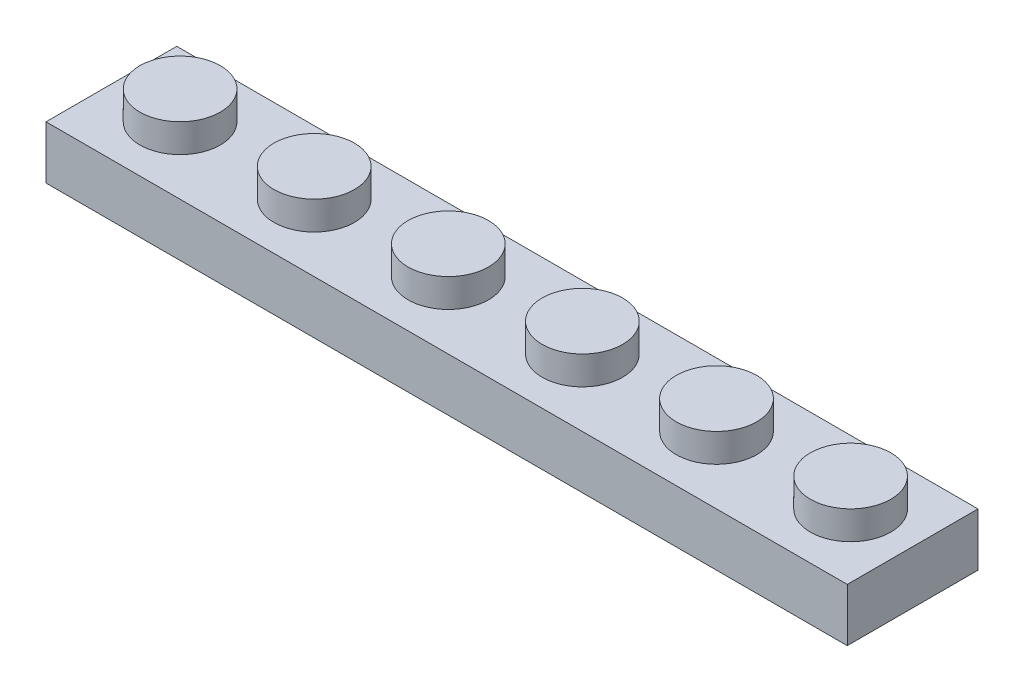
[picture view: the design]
ISO-10303-21;
HEADER;
FILE_DESCRIPTION(('STEP AP214'),'2;1');
FILE_NAME('part.step','',(''),(''),'','','');
FILE_SCHEMA(('AUTOMOTIVE_DESIGN { 1 0 10303 214 1 1 1 1 }'));
ENDSEC;
DATA;
#1=APPLICATION_CONTEXT('core data for automotive mechanical design processes');
#2=APPLICATION_PROTOCOL_DEFINITION('international standard','automotive_design',2000,#1);
#3=PRODUCT_CONTEXT('',#1,'mechanical');
#4=PRODUCT('Part','Part','',(#3));
#5=PRODUCT_RELATED_PRODUCT_CATEGORY('part','',(#4));
#6=PRODUCT_DEFINITION_FORMATION('','',#4);
#7=PRODUCT_DEFINITION_CONTEXT('part definition',#1,'design');
#8=PRODUCT_DEFINITION('design','',#6,#7);
#9=PRODUCT_DEFINITION_SHAPE('','',#8);
#10=(LENGTH_UNIT() NAMED_UNIT(*) SI_UNIT(.MILLI.,.METRE.));
#11=(NAMED_UNIT(*) PLANE_ANGLE_UNIT() SI_UNIT($,.RADIAN.));
#12=(NAMED_UNIT(*) SI_UNIT($,.STERADIAN.) SOLID_ANGLE_UNIT());
#13=UNCERTAINTY_MEASURE_WITH_UNIT(LENGTH_MEASURE(1.E-05),#10,'distance_accuracy_value','');
#14=(GEOMETRIC_REPRESENTATION_CONTEXT(3) GLOBAL_UNCERTAINTY_ASSIGNED_CONTEXT((#13)) GLOBAL_UNIT_ASSIGNED_CONTEXT((#10,
#11,#12)) REPRESENTATION_CONTEXT('',''));
#15=CARTESIAN_POINT('',(0.,0.,0.));
#16=DIRECTION('',(0.,0.,1.));
#17=DIRECTION('',(1.,0.,0.));
#18=AXIS2_PLACEMENT_3D('',#15,#16,#17);
#19=CARTESIAN_POINT('',(0.,3.166,-7.8));
#20=DIRECTION('',(0.,-1.,0.));
#21=DIRECTION('',(0.,0.,-1.));
#22=AXIS2_PLACEMENT_3D('',#19,#20,#21);
#23=PLANE('',#22);
#24=CARTESIAN_POINT('',(36.,3.166,-4.));
#25=DIRECTION('',(0.,-1.,0.));
#26=DIRECTION('',(0.,0.,-1.));
#27=AXIS2_PLACEMENT_3D('',#24,#25,#26);
#28=CIRCLE('',#27,2.4);
#29=CARTESIAN_POINT('',(36.,3.166,-6.4));
#30=VERTEX_POINT('',#29);
#31=EDGE_CURVE('E356',#30,#30,#28,.F.);
#32=ORIENTED_EDGE('',*,*,#31,.F.);
#33=EDGE_LOOP('',(#32));
#34=FACE_BOUND('',#33,.T.);
#35=CARTESIAN_POINT('',(20.,3.166,-4.));
#36=DIRECTION('',(0.,-1.,0.));
#37=DIRECTION('',(0.,0.,-1.));
#38=AXIS2_PLACEMENT_3D('',#35,#36,#37);
#39=CIRCLE('',#38,2.4);
#40=CARTESIAN_POINT('',(20.,3.166,-6.4));
#41=VERTEX_POINT('',#40);
#42=EDGE_CURVE('E350',#41,#41,#39,.F.);
#43=ORIENTED_EDGE('',*,*,#42,.F.);
#44=EDGE_LOOP('',(#43));
#45=FACE_BOUND('',#44,.T.);
#46=CARTESIAN_POINT('',(4.,3.166,-4.));
#47=DIRECTION('',(0.,-1.,0.));
#48=DIRECTION('',(0.,0.,-1.));
#49=AXIS2_PLACEMENT_3D('',#46,#47,#48);
#50=CIRCLE('',#49,2.4);
#51=CARTESIAN_POINT('',(4.,3.166,-6.4));
#52=VERTEX_POINT('',#51);
#53=EDGE_CURVE('E344',#52,#52,#50,.F.);
#54=ORIENTED_EDGE('',*,*,#53,.F.);
#55=EDGE_LOOP('',(#54));
#56=FACE_BOUND('',#55,.T.);
#57=DIRECTION('',(0.,0.,1.));
#58=VECTOR('',#57,1.);
#59=CARTESIAN_POINT('',(0.,3.166,0.));
#60=LINE('',#59,#58);
#61=CARTESIAN_POINT('',(0.,3.166,-7.8));
#62=VERTEX_POINT('',#61);
#63=CARTESIAN_POINT('',(0.,3.166,0.));
#64=VERTEX_POINT('',#63);
#65=EDGE_CURVE('E315',#62,#64,#60,.T.);
#66=ORIENTED_EDGE('',*,*,#65,.T.);
#67=DIRECTION('',(1.,0.,0.));
#68=VECTOR('',#67,1.);
#69=CARTESIAN_POINT('',(0.,3.166,0.));
#70=LINE('',#69,#68);
#71=CARTESIAN_POINT('',(47.8,3.166,0.));
#72=VERTEX_POINT('',#71);
#73=EDGE_CURVE('E318',#64,#72,#70,.T.);
#74=ORIENTED_EDGE('',*,*,#73,.T.);
#75=DIRECTION('',(0.,0.,-1.));
#76=VECTOR('',#75,1.);
#77=CARTESIAN_POINT('',(47.8,3.166,0.));
#78=LINE('',#77,#76);
#79=CARTESIAN_POINT('',(47.8,3.166,-7.8));
#80=VERTEX_POINT('',#79);
#81=EDGE_CURVE('E321',#72,#80,#78,.T.);
#82=ORIENTED_EDGE('',*,*,#81,.T.);
#83=DIRECTION('',(-1.,0.,0.));
#84=VECTOR('',#83,1.);
#85=CARTESIAN_POINT('',(0.,3.166,-7.8));
#86=LINE('',#85,#84);
#87=EDGE_CURVE('E323',#80,#62,#86,.T.);
#88=ORIENTED_EDGE('',*,*,#87,.T.);
#89=EDGE_LOOP('',(#66,#74,#82,#88));
#90=FACE_BOUND('',#89,.T.);
#91=CARTESIAN_POINT('',(12.,3.166,-4.));
#92=DIRECTION('',(0.,-1.,0.));
#93=DIRECTION('',(0.,0.,-1.));
#94=AXIS2_PLACEMENT_3D('',#91,#92,#93);
#95=CIRCLE('',#94,2.4);
#96=CARTESIAN_POINT('',(12.,3.166,-6.4));
#97=VERTEX_POINT('',#96);
#98=EDGE_CURVE('E347',#97,#97,#95,.F.);
#99=ORIENTED_EDGE('',*,*,#98,.F.);
#100=EDGE_LOOP('',(#99));
#101=FACE_BOUND('',#100,.T.);
#102=CARTESIAN_POINT('',(28.,3.166,-4.));
#103=DIRECTION('',(0.,-1.,0.));
#104=DIRECTION('',(0.,0.,-1.));
#105=AXIS2_PLACEMENT_3D('',#102,#103,#104);
#106=CIRCLE('',#105,2.4);
#107=CARTESIAN_POINT('',(28.,3.166,-6.4));
#108=VERTEX_POINT('',#107);
#109=EDGE_CURVE('E353',#108,#108,#106,.F.);
#110=ORIENTED_EDGE('',*,*,#109,.F.);
#111=EDGE_LOOP('',(#110));
#112=FACE_BOUND('',#111,.T.);
#113=CARTESIAN_POINT('',(44.,3.166,-4.));
#114=DIRECTION('',(0.,-1.,0.));
#115=DIRECTION('',(0.,0.,-1.));
#116=AXIS2_PLACEMENT_3D('',#113,#114,#115);
#117=CIRCLE('',#116,2.4);
#118=CARTESIAN_POINT('',(44.,3.166,-6.4));
#119=VERTEX_POINT('',#118);
#120=EDGE_CURVE('E359',#119,#119,#117,.F.);
#121=ORIENTED_EDGE('',*,*,#120,.F.);
#122=EDGE_LOOP('',(#121));
#123=FACE_BOUND('',#122,.T.);
#124=ADVANCED_FACE('F37',(#34,#45,#56,#90,#101,#112,#123),#23,.F.);
#125=CARTESIAN_POINT('',(0.,3.166,0.));
#126=DIRECTION('',(1.,0.,0.));
#127=DIRECTION('',(0.,0.,-1.));
#128=AXIS2_PLACEMENT_3D('',#125,#126,#127);
#129=PLANE('',#128);
#130=DIRECTION('',(0.,0.,1.));
#131=VECTOR('',#130,1.);
#132=CARTESIAN_POINT('',(0.,0.,0.));
#133=LINE('',#132,#131);
#134=CARTESIAN_POINT('',(0.,0.,-7.8));
#135=VERTEX_POINT('',#134);
#136=CARTESIAN_POINT('',(0.,0.,0.));
#137=VERTEX_POINT('',#136);
#138=EDGE_CURVE('E314',#135,#137,#133,.T.);
#139=ORIENTED_EDGE('',*,*,#138,.T.);
#140=DIRECTION('',(0.,-1.,0.));
#141=VECTOR('',#140,1.);
#142=CARTESIAN_POINT('',(0.,3.166,0.));
#143=LINE('',#142,#141);
#144=EDGE_CURVE('E341',#64,#137,#143,.T.);
#145=ORIENTED_EDGE('',*,*,#144,.F.);
#146=ORIENTED_EDGE('',*,*,#65,.F.);
#147=DIRECTION('',(0.,-1.,0.));
#148=VECTOR('',#147,1.);
#149=CARTESIAN_POINT('',(0.,3.166,-7.8));
#150=LINE('',#149,#148);
#151=EDGE_CURVE('E325',#62,#135,#150,.T.);
#152=ORIENTED_EDGE('',*,*,#151,.T.);
#153=EDGE_LOOP('',(#139,#145,#146,#152));
#154=FACE_BOUND('',#153,.T.);
#155=ADVANCED_FACE('F519',(#154),#129,.F.);
#156=CARTESIAN_POINT('',(0.,3.166,0.));
#157=DIRECTION('',(0.,0.,-1.));
#158=DIRECTION('',(-1.,0.,0.));
#159=AXIS2_PLACEMENT_3D('',#156,#157,#158);
#160=PLANE('',#159);
#161=DIRECTION('',(1.,0.,0.));
#162=VECTOR('',#161,1.);
#163=CARTESIAN_POINT('',(0.,0.,0.));
#164=LINE('',#163,#162);
#165=CARTESIAN_POINT('',(47.8,0.,0.));
#166=VERTEX_POINT('',#165);
#167=EDGE_CURVE('E328',#137,#166,#164,.T.);
#168=ORIENTED_EDGE('',*,*,#167,.T.);
#169=DIRECTION('',(0.,-1.,0.));
#170=VECTOR('',#169,1.);
#171=CARTESIAN_POINT('',(47.8,3.166,0.));
#172=LINE('',#171,#170);
#173=EDGE_CURVE('E338',#72,#166,#172,.T.);
#174=ORIENTED_EDGE('',*,*,#173,.F.);
#175=ORIENTED_EDGE('',*,*,#73,.F.);
#176=ORIENTED_EDGE('',*,*,#144,.T.);
#177=EDGE_LOOP('',(#168,#174,#175,#176));
#178=FACE_BOUND('',#177,.T.);
#179=ADVANCED_FACE('F524',(#178),#160,.F.);
#180=CARTESIAN_POINT('',(47.8,3.166,0.));
#181=DIRECTION('',(-1.,0.,0.));
#182=DIRECTION('',(0.,0.,1.));
#183=AXIS2_PLACEMENT_3D('',#180,#181,#182);
#184=PLANE('',#183);
#185=DIRECTION('',(0.,0.,-1.));
#186=VECTOR('',#185,1.);
#187=CARTESIAN_POINT('',(47.8,0.,0.));
#188=LINE('',#187,#186);
#189=CARTESIAN_POINT('',(47.8,0.,-7.8));
#190=VERTEX_POINT('',#189);
#191=EDGE_CURVE('E330',#166,#190,#188,.T.);
#192=ORIENTED_EDGE('',*,*,#191,.T.);
#193=DIRECTION('',(0.,-1.,0.));
#194=VECTOR('',#193,1.);
#195=CARTESIAN_POINT('',(47.8,3.166,-7.8));
#196=LINE('',#195,#194);
#197=EDGE_CURVE('E335',#80,#190,#196,.T.);
#198=ORIENTED_EDGE('',*,*,#197,.F.);
#199=ORIENTED_EDGE('',*,*,#81,.F.);
#200=ORIENTED_EDGE('',*,*,#173,.T.);
#201=EDGE_LOOP('',(#192,#198,#199,#200));
#202=FACE_BOUND('',#201,.T.);
#203=ADVANCED_FACE('F513',(#202),#184,.F.);
#204=CARTESIAN_POINT('',(0.,3.166,-7.8));
#205=DIRECTION('',(0.,0.,1.));
#206=DIRECTION('',(1.,0.,0.));
#207=AXIS2_PLACEMENT_3D('',#204,#205,#206);
#208=PLANE('',#207);
#209=DIRECTION('',(-1.,0.,0.));
#210=VECTOR('',#209,1.);
#211=CARTESIAN_POINT('',(0.,0.,-7.8));
#212=LINE('',#211,#210);
#213=EDGE_CURVE('E319',#190,#135,#212,.T.);
#214=ORIENTED_EDGE('',*,*,#213,.T.);
#215=ORIENTED_EDGE('',*,*,#151,.F.);
#216=ORIENTED_EDGE('',*,*,#87,.F.);
#217=ORIENTED_EDGE('',*,*,#197,.T.);
#218=EDGE_LOOP('',(#214,#215,#216,#217));
#219=FACE_BOUND('',#218,.T.);
#220=ADVANCED_FACE('F503',(#219),#208,.F.);
#221=CARTESIAN_POINT('',(0.,0.,-7.8));
#222=DIRECTION('',(0.,-1.,0.));
#223=DIRECTION('',(0.,0.,-1.));
#224=AXIS2_PLACEMENT_3D('',#221,#222,#223);
#225=PLANE('',#224);
#226=DIRECTION('',(0.,0.,-1.));
#227=VECTOR('',#226,1.);
#228=CARTESIAN_POINT('',(33.55,0.,-1.55));
#229=LINE('',#228,#227);
#230=CARTESIAN_POINT('',(33.55,0.,-1.55));
#231=VERTEX_POINT('',#230);
#232=CARTESIAN_POINT('',(33.55,0.,-6.35));
#233=VERTEX_POINT('',#232);
#234=EDGE_CURVE('E249',#231,#233,#229,.T.);
#235=ORIENTED_EDGE('',*,*,#234,.F.);
#236=DIRECTION('',(-1.,0.,0.));
#237=VECTOR('',#236,1.);
#238=CARTESIAN_POINT('',(33.55,0.,-1.55));
#239=LINE('',#238,#237);
#240=CARTESIAN_POINT('',(38.35,0.,-1.55));
#241=VERTEX_POINT('',#240);
#242=EDGE_CURVE('E259',#241,#231,#239,.T.);
#243=ORIENTED_EDGE('',*,*,#242,.F.);
#244=DIRECTION('',(0.,0.,1.));
#245=VECTOR('',#244,1.);
#246=CARTESIAN_POINT('',(38.35,0.,-1.55));
#247=LINE('',#246,#245);
#248=CARTESIAN_POINT('',(38.35,0.,-6.35));
#249=VERTEX_POINT('',#248);
#250=EDGE_CURVE('E250',#249,#241,#247,.T.);
#251=ORIENTED_EDGE('',*,*,#250,.F.);
#252=DIRECTION('',(1.,0.,0.));
#253=VECTOR('',#252,1.);
#254=CARTESIAN_POINT('',(33.55,0.,-6.35));
#255=LINE('',#254,#253);
#256=EDGE_CURVE('E235',#233,#249,#255,.T.);
#257=ORIENTED_EDGE('',*,*,#256,.F.);
#258=EDGE_LOOP('',(#235,#243,#251,#257));
#259=FACE_BOUND('',#258,.T.);
#260=DIRECTION('',(0.,0.,-1.));
#261=VECTOR('',#260,1.);
#262=CARTESIAN_POINT('',(41.55,0.,-1.55));
#263=LINE('',#262,#261);
#264=CARTESIAN_POINT('',(41.55,0.,-1.55));
#265=VERTEX_POINT('',#264);
#266=CARTESIAN_POINT('',(41.55,0.,-6.35));
#267=VERTEX_POINT('',#266);
#268=EDGE_CURVE('E279',#265,#267,#263,.T.);
#269=ORIENTED_EDGE('',*,*,#268,.F.);
#270=DIRECTION('',(-1.,0.,0.));
#271=VECTOR('',#270,1.);
#272=CARTESIAN_POINT('',(41.55,0.,-1.55));
#273=LINE('',#272,#271);
#274=CARTESIAN_POINT('',(46.35,0.,-1.55));
#275=VERTEX_POINT('',#274);
#276=EDGE_CURVE('E284',#275,#265,#273,.T.);
#277=ORIENTED_EDGE('',*,*,#276,.F.);
#278=DIRECTION('',(0.,0.,1.));
#279=VECTOR('',#278,1.);
#280=CARTESIAN_POINT('',(46.35,0.,-1.55));
#281=LINE('',#280,#279);
#282=CARTESIAN_POINT('',(46.35,0.,-6.35));
#283=VERTEX_POINT('',#282);
#284=EDGE_CURVE('E298',#283,#275,#281,.T.);
#285=ORIENTED_EDGE('',*,*,#284,.F.);
#286=DIRECTION('',(1.,0.,0.));
#287=VECTOR('',#286,1.);
#288=CARTESIAN_POINT('',(41.55,0.,-6.35));
#289=LINE('',#288,#287);
#290=EDGE_CURVE('E295',#267,#283,#289,.T.);
#291=ORIENTED_EDGE('',*,*,#290,.F.);
#292=EDGE_LOOP('',(#269,#277,#285,#291));
#293=FACE_BOUND('',#292,.T.);
#294=ORIENTED_EDGE('',*,*,#138,.F.);
#295=ORIENTED_EDGE('',*,*,#213,.F.);
#296=ORIENTED_EDGE('',*,*,#191,.F.);
#297=ORIENTED_EDGE('',*,*,#167,.F.);
#298=EDGE_LOOP('',(#294,#295,#296,#297));
#299=FACE_BOUND('',#298,.T.);
#300=DIRECTION('',(0.,0.,-1.));
#301=VECTOR('',#300,1.);
#302=CARTESIAN_POINT('',(25.55,0.,-1.55));
#303=LINE('',#302,#301);
#304=CARTESIAN_POINT('',(25.55,0.,-1.55));
#305=VERTEX_POINT('',#304);
#306=CARTESIAN_POINT('',(25.55,0.,-6.35));
#307=VERTEX_POINT('',#306);
#308=EDGE_CURVE('E362',#305,#307,#303,.T.);
#309=ORIENTED_EDGE('',*,*,#308,.F.);
#310=DIRECTION('',(-1.,0.,0.));
#311=VECTOR('',#310,1.);
#312=CARTESIAN_POINT('',(25.55,0.,-1.55));
#313=LINE('',#312,#311);
#314=CARTESIAN_POINT('',(30.35,0.,-1.55));
#315=VERTEX_POINT('',#314);
#316=EDGE_CURVE('E364',#315,#305,#313,.T.);
#317=ORIENTED_EDGE('',*,*,#316,.F.);
#318=DIRECTION('',(0.,0.,1.));
#319=VECTOR('',#318,1.);
#320=CARTESIAN_POINT('',(30.35,0.,-1.55));
#321=LINE('',#320,#319);
#322=CARTESIAN_POINT('',(30.35,0.,-6.35));
#323=VERTEX_POINT('',#322);
#324=EDGE_CURVE('E367',#323,#315,#321,.T.);
#325=ORIENTED_EDGE('',*,*,#324,.F.);
#326=DIRECTION('',(1.,0.,0.));
#327=VECTOR('',#326,1.);
#328=CARTESIAN_POINT('',(25.55,0.,-6.35));
#329=LINE('',#328,#327);
#330=EDGE_CURVE('E370',#307,#323,#329,.T.);
#331=ORIENTED_EDGE('',*,*,#330,.F.);
#332=EDGE_LOOP('',(#309,#317,#325,#331));
#333=FACE_BOUND('',#332,.T.);
#334=DIRECTION('',(0.,0.,-1.));
#335=VECTOR('',#334,1.);
#336=CARTESIAN_POINT('',(17.55,0.,-1.55));
#337=LINE('',#336,#335);
#338=CARTESIAN_POINT('',(17.55,0.,-1.55));
#339=VERTEX_POINT('',#338);
#340=CARTESIAN_POINT('',(17.55,0.,-6.35));
#341=VERTEX_POINT('',#340);
#342=EDGE_CURVE('E397',#339,#341,#337,.T.);
#343=ORIENTED_EDGE('',*,*,#342,.F.);
#344=DIRECTION('',(-1.,0.,0.));
#345=VECTOR('',#344,1.);
#346=CARTESIAN_POINT('',(17.55,0.,-1.55));
#347=LINE('',#346,#345);
#348=CARTESIAN_POINT('',(22.35,0.,-1.55));
#349=VERTEX_POINT('',#348);
#350=EDGE_CURVE('E399',#349,#339,#347,.T.);
#351=ORIENTED_EDGE('',*,*,#350,.F.);
#352=DIRECTION('',(0.,0.,1.));
#353=VECTOR('',#352,1.);
#354=CARTESIAN_POINT('',(22.35,0.,-1.55));
#355=LINE('',#354,#353);
#356=CARTESIAN_POINT('',(22.35,0.,-6.35));
#357=VERTEX_POINT('',#356);
#358=EDGE_CURVE('E402',#357,#349,#355,.T.);
#359=ORIENTED_EDGE('',*,*,#358,.F.);
#360=DIRECTION('',(1.,0.,0.));
#361=VECTOR('',#360,1.);
#362=CARTESIAN_POINT('',(17.55,0.,-6.35));
#363=LINE('',#362,#361);
#364=EDGE_CURVE('E405',#341,#357,#363,.T.);
#365=ORIENTED_EDGE('',*,*,#364,.F.);
#366=EDGE_LOOP('',(#343,#351,#359,#365));
#367=FACE_BOUND('',#366,.T.);
#368=DIRECTION('',(0.,0.,-1.));
#369=VECTOR('',#368,1.);
#370=CARTESIAN_POINT('',(9.55,0.,-1.55));
#371=LINE('',#370,#369);
#372=CARTESIAN_POINT('',(9.55,0.,-1.55));
#373=VERTEX_POINT('',#372);
#374=CARTESIAN_POINT('',(9.55,0.,-6.35));
#375=VERTEX_POINT('',#374);
#376=EDGE_CURVE('E432',#373,#375,#371,.T.);
#377=ORIENTED_EDGE('',*,*,#376,.F.);
#378=DIRECTION('',(-1.,0.,0.));
#379=VECTOR('',#378,1.);
#380=CARTESIAN_POINT('',(9.55,0.,-1.55));
#381=LINE('',#380,#379);
#382=CARTESIAN_POINT('',(14.35,0.,-1.55));
#383=VERTEX_POINT('',#382);
#384=EDGE_CURVE('E434',#383,#373,#381,.T.);
#385=ORIENTED_EDGE('',*,*,#384,.F.);
#386=DIRECTION('',(0.,0.,1.));
#387=VECTOR('',#386,1.);
#388=CARTESIAN_POINT('',(14.35,0.,-1.55));
#389=LINE('',#388,#387);
#390=CARTESIAN_POINT('',(14.35,0.,-6.35));
#391=VERTEX_POINT('',#390);
#392=EDGE_CURVE('E437',#391,#383,#389,.T.);
#393=ORIENTED_EDGE('',*,*,#392,.F.);
#394=DIRECTION('',(1.,0.,0.));
#395=VECTOR('',#394,1.);
#396=CARTESIAN_POINT('',(9.55,0.,-6.35));
#397=LINE('',#396,#395);
#398=EDGE_CURVE('E440',#375,#391,#397,.T.);
#399=ORIENTED_EDGE('',*,*,#398,.F.);
#400=EDGE_LOOP('',(#377,#385,#393,#399));
#401=FACE_BOUND('',#400,.T.);
#402=DIRECTION('',(0.,0.,-1.));
#403=VECTOR('',#402,1.);
#404=CARTESIAN_POINT('',(1.55,0.,-1.55));
#405=LINE('',#404,#403);
#406=CARTESIAN_POINT('',(1.55,0.,-1.55));
#407=VERTEX_POINT('',#406);
#408=CARTESIAN_POINT('',(1.55,0.,-6.35));
#409=VERTEX_POINT('',#408);
#410=EDGE_CURVE('E467',#407,#409,#405,.T.);
#411=ORIENTED_EDGE('',*,*,#410,.F.);
#412=DIRECTION('',(-1.,0.,0.));
#413=VECTOR('',#412,1.);
#414=CARTESIAN_POINT('',(1.55,0.,-1.55));
#415=LINE('',#414,#413);
#416=CARTESIAN_POINT('',(6.34999999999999,0.,-1.55));
#417=VERTEX_POINT('',#416);
#418=EDGE_CURVE('E469',#417,#407,#415,.T.);
#419=ORIENTED_EDGE('',*,*,#418,.F.);
#420=DIRECTION('',(0.,0.,1.));
#421=VECTOR('',#420,1.);
#422=CARTESIAN_POINT('',(6.34999999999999,0.,-1.55));
#423=LINE('',#422,#421);
#424=CARTESIAN_POINT('',(6.34999999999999,0.,-6.35));
#425=VERTEX_POINT('',#424);
#426=EDGE_CURVE('E472',#425,#417,#423,.T.);
#427=ORIENTED_EDGE('',*,*,#426,.F.);
#428=DIRECTION('',(1.,0.,0.));
#429=VECTOR('',#428,1.);
#430=CARTESIAN_POINT('',(1.55,0.,-6.35));
#431=LINE('',#430,#429);
#432=EDGE_CURVE('E475',#409,#425,#431,.T.);
#433=ORIENTED_EDGE('',*,*,#432,.F.);
#434=EDGE_LOOP('',(#411,#419,#427,#433));
#435=FACE_BOUND('',#434,.T.);
#436=ADVANCED_FACE('F500',(#259,#293,#299,#333,#367,#401,#435),#225,.T.);
#437=CARTESIAN_POINT('',(4.,4.866,-4.));
#438=DIRECTION('',(0.,-1.,0.));
#439=DIRECTION('',(0.,0.,-1.));
#440=AXIS2_PLACEMENT_3D('',#437,#438,#439);
#441=CYLINDRICAL_SURFACE('',#440,2.4);
#442=CARTESIAN_POINT('',(4.,4.866,-4.));
#443=DIRECTION('',(0.,1.,0.));
#444=DIRECTION('',(0.,0.,1.));
#445=AXIS2_PLACEMENT_3D('',#442,#443,#444);
#446=CIRCLE('',#445,2.4);
#447=CARTESIAN_POINT('',(4.,4.866,-1.6));
#448=VERTEX_POINT('',#447);
#449=EDGE_CURVE('E305',#448,#448,#446,.T.);
#450=ORIENTED_EDGE('',*,*,#449,.F.);
#451=EDGE_LOOP('',(#450));
#452=FACE_BOUND('',#451,.T.);
#453=ORIENTED_EDGE('',*,*,#53,.T.);
#454=EDGE_LOOP('',(#453));
#455=FACE_BOUND('',#454,.T.);
#456=ADVANCED_FACE('F502',(#452,#455),#441,.T.);
#457=CARTESIAN_POINT('',(4.,4.866,-4.));
#458=DIRECTION('',(0.,1.,0.));
#459=DIRECTION('',(0.,0.,1.));
#460=AXIS2_PLACEMENT_3D('',#457,#458,#459);
#461=PLANE('',#460);
#462=ORIENTED_EDGE('',*,*,#449,.T.);
#463=EDGE_LOOP('',(#462));
#464=FACE_BOUND('',#463,.T.);
#465=ADVANCED_FACE('F510',(#464),#461,.T.);
#466=CARTESIAN_POINT('',(41.55,1.8,-1.55));
#467=DIRECTION('',(-1.,0.,0.));
#468=DIRECTION('',(0.,0.,1.));
#469=AXIS2_PLACEMENT_3D('',#466,#467,#468);
#470=PLANE('',#469);
#471=ORIENTED_EDGE('',*,*,#268,.T.);
#472=DIRECTION('',(0.,-1.,0.));
#473=VECTOR('',#472,1.);
#474=CARTESIAN_POINT('',(41.55,1.8,-6.35));
#475=LINE('',#474,#473);
#476=CARTESIAN_POINT('',(41.55,1.8,-6.35));
#477=VERTEX_POINT('',#476);
#478=EDGE_CURVE('E293',#477,#267,#475,.T.);
#479=ORIENTED_EDGE('',*,*,#478,.F.);
#480=DIRECTION('',(0.,0.,-1.));
#481=VECTOR('',#480,1.);
#482=CARTESIAN_POINT('',(41.55,1.8,-1.55));
#483=LINE('',#482,#481);
#484=CARTESIAN_POINT('',(41.55,1.8,-1.55));
#485=VERTEX_POINT('',#484);
#486=EDGE_CURVE('E280',#485,#477,#483,.T.);
#487=ORIENTED_EDGE('',*,*,#486,.F.);
#488=DIRECTION('',(0.,-1.,0.));
#489=VECTOR('',#488,1.);
#490=CARTESIAN_POINT('',(41.55,1.8,-1.55));
#491=LINE('',#490,#489);
#492=EDGE_CURVE('E303',#485,#265,#491,.T.);
#493=ORIENTED_EDGE('',*,*,#492,.T.);
#494=EDGE_LOOP('',(#471,#479,#487,#493));
#495=FACE_BOUND('',#494,.T.);
#496=ADVANCED_FACE('F532',(#495),#470,.F.);
#497=CARTESIAN_POINT('',(41.55,1.8,-1.55));
#498=DIRECTION('',(0.,0.,1.));
#499=DIRECTION('',(1.,0.,0.));
#500=AXIS2_PLACEMENT_3D('',#497,#498,#499);
#501=PLANE('',#500);
#502=ORIENTED_EDGE('',*,*,#276,.T.);
#503=ORIENTED_EDGE('',*,*,#492,.F.);
#504=DIRECTION('',(-1.,0.,0.));
#505=VECTOR('',#504,1.);
#506=CARTESIAN_POINT('',(41.55,1.8,-1.55));
#507=LINE('',#506,#505);
#508=CARTESIAN_POINT('',(46.35,1.8,-1.55));
#509=VERTEX_POINT('',#508);
#510=EDGE_CURVE('E290',#509,#485,#507,.T.);
#511=ORIENTED_EDGE('',*,*,#510,.F.);
#512=DIRECTION('',(0.,-1.,0.));
#513=VECTOR('',#512,1.);
#514=CARTESIAN_POINT('',(46.35,1.8,-1.55));
#515=LINE('',#514,#513);
#516=EDGE_CURVE('E306',#509,#275,#515,.T.);
#517=ORIENTED_EDGE('',*,*,#516,.T.);
#518=EDGE_LOOP('',(#502,#503,#511,#517));
#519=FACE_BOUND('',#518,.T.);
#520=ADVANCED_FACE('F536',(#519),#501,.F.);
#521=CARTESIAN_POINT('',(46.35,1.8,-1.55));
#522=DIRECTION('',(1.,0.,0.));
#523=DIRECTION('',(0.,0.,-1.));
#524=AXIS2_PLACEMENT_3D('',#521,#522,#523);
#525=PLANE('',#524);
#526=ORIENTED_EDGE('',*,*,#284,.T.);
#527=ORIENTED_EDGE('',*,*,#516,.F.);
#528=DIRECTION('',(0.,0.,1.));
#529=VECTOR('',#528,1.);
#530=CARTESIAN_POINT('',(46.35,1.8,-1.55));
#531=LINE('',#530,#529);
#532=CARTESIAN_POINT('',(46.35,1.8,-6.35));
#533=VERTEX_POINT('',#532);
#534=EDGE_CURVE('E287',#533,#509,#531,.T.);
#535=ORIENTED_EDGE('',*,*,#534,.F.);
#536=DIRECTION('',(0.,-1.,0.));
#537=VECTOR('',#536,1.);
#538=CARTESIAN_POINT('',(46.35,1.8,-6.35));
#539=LINE('',#538,#537);
#540=EDGE_CURVE('E308',#533,#283,#539,.T.);
#541=ORIENTED_EDGE('',*,*,#540,.T.);
#542=EDGE_LOOP('',(#526,#527,#535,#541));
#543=FACE_BOUND('',#542,.T.);
#544=ADVANCED_FACE('F542',(#543),#525,.F.);
#545=CARTESIAN_POINT('',(41.55,1.8,-6.35));
#546=DIRECTION('',(0.,0.,-1.));
#547=DIRECTION('',(-1.,0.,0.));
#548=AXIS2_PLACEMENT_3D('',#545,#546,#547);
#549=PLANE('',#548);
#550=ORIENTED_EDGE('',*,*,#290,.T.);
#551=ORIENTED_EDGE('',*,*,#540,.F.);
#552=DIRECTION('',(1.,0.,0.));
#553=VECTOR('',#552,1.);
#554=CARTESIAN_POINT('',(41.55,1.8,-6.35));
#555=LINE('',#554,#553);
#556=EDGE_CURVE('E283',#477,#533,#555,.T.);
#557=ORIENTED_EDGE('',*,*,#556,.F.);
#558=ORIENTED_EDGE('',*,*,#478,.T.);
#559=EDGE_LOOP('',(#550,#551,#557,#558));
#560=FACE_BOUND('',#559,.T.);
#561=ADVANCED_FACE('F538',(#560),#549,.F.);
#562=CARTESIAN_POINT('',(41.55,1.8,-6.35));
#563=DIRECTION('',(0.,-1.,0.));
#564=DIRECTION('',(0.,0.,-1.));
#565=AXIS2_PLACEMENT_3D('',#562,#563,#564);
#566=PLANE('',#565);
#567=ORIENTED_EDGE('',*,*,#486,.T.);
#568=ORIENTED_EDGE('',*,*,#556,.T.);
#569=ORIENTED_EDGE('',*,*,#534,.T.);
#570=ORIENTED_EDGE('',*,*,#510,.T.);
#571=EDGE_LOOP('',(#567,#568,#569,#570));
#572=FACE_BOUND('',#571,.T.);
#573=ADVANCED_FACE('F541',(#572),#566,.T.);
#574=CARTESIAN_POINT('',(12.,4.866,-4.));
#575=DIRECTION('',(0.,-1.,0.));
#576=DIRECTION('',(0.,0.,-1.));
#577=AXIS2_PLACEMENT_3D('',#574,#575,#576);
#578=CYLINDRICAL_SURFACE('',#577,2.4);
#579=CARTESIAN_POINT('',(12.,4.866,-4.));
#580=DIRECTION('',(0.,1.,0.));
#581=DIRECTION('',(0.,0.,1.));
#582=AXIS2_PLACEMENT_3D('',#579,#580,#581);
#583=CIRCLE('',#582,2.4);
#584=CARTESIAN_POINT('',(12.,4.866,-1.6));
#585=VERTEX_POINT('',#584);
#586=EDGE_CURVE('E276',#585,#585,#583,.T.);
#587=ORIENTED_EDGE('',*,*,#586,.F.);
#588=EDGE_LOOP('',(#587));
#589=FACE_BOUND('',#588,.T.);
#590=ORIENTED_EDGE('',*,*,#98,.T.);
#591=EDGE_LOOP('',(#590));
#592=FACE_BOUND('',#591,.T.);
#593=ADVANCED_FACE('F552',(#589,#592),#578,.T.);
#594=CARTESIAN_POINT('',(12.,4.866,-4.));
#595=DIRECTION('',(0.,1.,0.));
#596=DIRECTION('',(0.,0.,1.));
#597=AXIS2_PLACEMENT_3D('',#594,#595,#596);
#598=PLANE('',#597);
#599=ORIENTED_EDGE('',*,*,#586,.T.);
#600=EDGE_LOOP('',(#599));
#601=FACE_BOUND('',#600,.T.);
#602=ADVANCED_FACE('F554',(#601),#598,.T.);
#603=CARTESIAN_POINT('',(20.,4.866,-4.));
#604=DIRECTION('',(0.,-1.,0.));
#605=DIRECTION('',(0.,0.,-1.));
#606=AXIS2_PLACEMENT_3D('',#603,#604,#605);
#607=CYLINDRICAL_SURFACE('',#606,2.4);
#608=CARTESIAN_POINT('',(20.,4.866,-4.));
#609=DIRECTION('',(0.,1.,0.));
#610=DIRECTION('',(0.,0.,1.));
#611=AXIS2_PLACEMENT_3D('',#608,#609,#610);
#612=CIRCLE('',#611,2.4);
#613=CARTESIAN_POINT('',(20.,4.866,-1.6));
#614=VERTEX_POINT('',#613);
#615=EDGE_CURVE('E273',#614,#614,#612,.T.);
#616=ORIENTED_EDGE('',*,*,#615,.F.);
#617=EDGE_LOOP('',(#616));
#618=FACE_BOUND('',#617,.T.);
#619=ORIENTED_EDGE('',*,*,#42,.T.);
#620=EDGE_LOOP('',(#619));
#621=FACE_BOUND('',#620,.T.);
#622=ADVANCED_FACE('F561',(#618,#621),#607,.T.);
#623=CARTESIAN_POINT('',(20.,4.866,-4.));
#624=DIRECTION('',(0.,1.,0.));
#625=DIRECTION('',(0.,0.,1.));
#626=AXIS2_PLACEMENT_3D('',#623,#624,#625);
#627=PLANE('',#626);
#628=ORIENTED_EDGE('',*,*,#615,.T.);
#629=EDGE_LOOP('',(#628));
#630=FACE_BOUND('',#629,.T.);
#631=ADVANCED_FACE('F558',(#630),#627,.T.);
#632=CARTESIAN_POINT('',(28.,4.866,-4.));
#633=DIRECTION('',(0.,-1.,0.));
#634=DIRECTION('',(0.,0.,-1.));
#635=AXIS2_PLACEMENT_3D('',#632,#633,#634);
#636=CYLINDRICAL_SURFACE('',#635,2.4);
#637=CARTESIAN_POINT('',(28.,4.866,-4.));
#638=DIRECTION('',(0.,1.,0.));
#639=DIRECTION('',(0.,0.,1.));
#640=AXIS2_PLACEMENT_3D('',#637,#638,#639);
#641=CIRCLE('',#640,2.4);
#642=CARTESIAN_POINT('',(28.,4.866,-1.6));
#643=VERTEX_POINT('',#642);
#644=EDGE_CURVE('E270',#643,#643,#641,.T.);
#645=ORIENTED_EDGE('',*,*,#644,.F.);
#646=EDGE_LOOP('',(#645));
#647=FACE_BOUND('',#646,.T.);
#648=ORIENTED_EDGE('',*,*,#109,.T.);
#649=EDGE_LOOP('',(#648));
#650=FACE_BOUND('',#649,.T.);
#651=ADVANCED_FACE('F569',(#647,#650),#636,.T.);
#652=CARTESIAN_POINT('',(28.,4.866,-4.));
#653=DIRECTION('',(0.,1.,0.));
#654=DIRECTION('',(0.,0.,1.));
#655=AXIS2_PLACEMENT_3D('',#652,#653,#654);
#656=PLANE('',#655);
#657=ORIENTED_EDGE('',*,*,#644,.T.);
#658=EDGE_LOOP('',(#657));
#659=FACE_BOUND('',#658,.T.);
#660=ADVANCED_FACE('F566',(#659),#656,.T.);
#661=CARTESIAN_POINT('',(36.,4.866,-4.));
#662=DIRECTION('',(0.,-1.,0.));
#663=DIRECTION('',(0.,0.,-1.));
#664=AXIS2_PLACEMENT_3D('',#661,#662,#663);
#665=CYLINDRICAL_SURFACE('',#664,2.4);
#666=CARTESIAN_POINT('',(36.,4.866,-4.));
#667=DIRECTION('',(0.,1.,0.));
#668=DIRECTION('',(0.,0.,1.));
#669=AXIS2_PLACEMENT_3D('',#666,#667,#668);
#670=CIRCLE('',#669,2.4);
#671=CARTESIAN_POINT('',(36.,4.866,-1.6));
#672=VERTEX_POINT('',#671);
#673=EDGE_CURVE('E267',#672,#672,#670,.T.);
#674=ORIENTED_EDGE('',*,*,#673,.F.);
#675=EDGE_LOOP('',(#674));
#676=FACE_BOUND('',#675,.T.);
#677=ORIENTED_EDGE('',*,*,#31,.T.);
#678=EDGE_LOOP('',(#677));
#679=FACE_BOUND('',#678,.T.);
#680=ADVANCED_FACE('F577',(#676,#679),#665,.T.);
#681=CARTESIAN_POINT('',(36.,4.866,-4.));
#682=DIRECTION('',(0.,1.,0.));
#683=DIRECTION('',(0.,0.,1.));
#684=AXIS2_PLACEMENT_3D('',#681,#682,#683);
#685=PLANE('',#684);
#686=ORIENTED_EDGE('',*,*,#673,.T.);
#687=EDGE_LOOP('',(#686));
#688=FACE_BOUND('',#687,.T.);
#689=ADVANCED_FACE('F574',(#688),#685,.T.);
#690=CARTESIAN_POINT('',(44.,4.866,-4.));
#691=DIRECTION('',(0.,-1.,0.));
#692=DIRECTION('',(0.,0.,-1.));
#693=AXIS2_PLACEMENT_3D('',#690,#691,#692);
#694=CYLINDRICAL_SURFACE('',#693,2.4);
#695=CARTESIAN_POINT('',(44.,4.866,-4.));
#696=DIRECTION('',(0.,1.,0.));
#697=DIRECTION('',(0.,0.,1.));
#698=AXIS2_PLACEMENT_3D('',#695,#696,#697);
#699=CIRCLE('',#698,2.4);
#700=CARTESIAN_POINT('',(44.,4.866,-1.6));
#701=VERTEX_POINT('',#700);
#702=EDGE_CURVE('E264',#701,#701,#699,.T.);
#703=ORIENTED_EDGE('',*,*,#702,.F.);
#704=EDGE_LOOP('',(#703));
#705=FACE_BOUND('',#704,.T.);
#706=ORIENTED_EDGE('',*,*,#120,.T.);
#707=EDGE_LOOP('',(#706));
#708=FACE_BOUND('',#707,.T.);
#709=ADVANCED_FACE('F585',(#705,#708),#694,.T.);
#710=CARTESIAN_POINT('',(44.,4.866,-4.));
#711=DIRECTION('',(0.,1.,0.));
#712=DIRECTION('',(0.,0.,1.));
#713=AXIS2_PLACEMENT_3D('',#710,#711,#712);
#714=PLANE('',#713);
#715=ORIENTED_EDGE('',*,*,#702,.T.);
#716=EDGE_LOOP('',(#715));
#717=FACE_BOUND('',#716,.T.);
#718=ADVANCED_FACE('F582',(#717),#714,.T.);
#719=CARTESIAN_POINT('',(33.55,1.8,-1.55));
#720=DIRECTION('',(-1.,0.,0.));
#721=DIRECTION('',(0.,0.,1.));
#722=AXIS2_PLACEMENT_3D('',#719,#720,#721);
#723=PLANE('',#722);
#724=ORIENTED_EDGE('',*,*,#234,.T.);
#725=DIRECTION('',(0.,-1.,0.));
#726=VECTOR('',#725,1.);
#727=CARTESIAN_POINT('',(33.55,1.8,-6.35));
#728=LINE('',#727,#726);
#729=CARTESIAN_POINT('',(33.55,1.8,-6.35));
#730=VERTEX_POINT('',#729);
#731=EDGE_CURVE('E241',#730,#233,#728,.T.);
#732=ORIENTED_EDGE('',*,*,#731,.F.);
#733=DIRECTION('',(0.,0.,-1.));
#734=VECTOR('',#733,1.);
#735=CARTESIAN_POINT('',(33.55,1.8,-1.55));
#736=LINE('',#735,#734);
#737=CARTESIAN_POINT('',(33.55,1.8,-1.55));
#738=VERTEX_POINT('',#737);
#739=EDGE_CURVE('E224',#738,#730,#736,.T.);
#740=ORIENTED_EDGE('',*,*,#739,.F.);
#741=DIRECTION('',(0.,-1.,0.));
#742=VECTOR('',#741,1.);
#743=CARTESIAN_POINT('',(33.55,1.8,-1.55));
#744=LINE('',#743,#742);
#745=EDGE_CURVE('E261',#738,#231,#744,.T.);
#746=ORIENTED_EDGE('',*,*,#745,.T.);
#747=EDGE_LOOP('',(#724,#732,#740,#746));
#748=FACE_BOUND('',#747,.T.);
#749=ADVANCED_FACE('F247',(#748),#723,.F.);
#750=CARTESIAN_POINT('',(33.55,1.8,-1.55));
#751=DIRECTION('',(0.,0.,1.));
#752=DIRECTION('',(1.,0.,0.));
#753=AXIS2_PLACEMENT_3D('',#750,#751,#752);
#754=PLANE('',#753);
#755=ORIENTED_EDGE('',*,*,#242,.T.);
#756=ORIENTED_EDGE('',*,*,#745,.F.);
#757=DIRECTION('',(-1.,0.,0.));
#758=VECTOR('',#757,1.);
#759=CARTESIAN_POINT('',(33.55,1.8,-1.55));
#760=LINE('',#759,#758);
#761=CARTESIAN_POINT('',(38.35,1.8,-1.55));
#762=VERTEX_POINT('',#761);
#763=EDGE_CURVE('E230',#762,#738,#760,.T.);
#764=ORIENTED_EDGE('',*,*,#763,.F.);
#765=DIRECTION('',(0.,-1.,0.));
#766=VECTOR('',#765,1.);
#767=CARTESIAN_POINT('',(38.35,1.8,-1.55));
#768=LINE('',#767,#766);
#769=EDGE_CURVE('E252',#762,#241,#768,.T.);
#770=ORIENTED_EDGE('',*,*,#769,.T.);
#771=EDGE_LOOP('',(#755,#756,#764,#770));
#772=FACE_BOUND('',#771,.T.);
#773=ADVANCED_FACE('F595',(#772),#754,.F.);
#774=CARTESIAN_POINT('',(38.35,1.8,-1.55));
#775=DIRECTION('',(1.,0.,0.));
#776=DIRECTION('',(0.,0.,-1.));
#777=AXIS2_PLACEMENT_3D('',#774,#775,#776);
#778=PLANE('',#777);
#779=ORIENTED_EDGE('',*,*,#250,.T.);
#780=ORIENTED_EDGE('',*,*,#769,.F.);
#781=DIRECTION('',(0.,0.,1.));
#782=VECTOR('',#781,1.);
#783=CARTESIAN_POINT('',(38.35,1.8,-1.55));
#784=LINE('',#783,#782);
#785=CARTESIAN_POINT('',(38.35,1.8,-6.35));
#786=VERTEX_POINT('',#785);
#787=EDGE_CURVE('E245',#786,#762,#784,.T.);
#788=ORIENTED_EDGE('',*,*,#787,.F.);
#789=DIRECTION('',(0.,-1.,0.));
#790=VECTOR('',#789,1.);
#791=CARTESIAN_POINT('',(38.35,1.8,-6.35));
#792=LINE('',#791,#790);
#793=EDGE_CURVE('E244',#786,#249,#792,.T.);
#794=ORIENTED_EDGE('',*,*,#793,.T.);
#795=EDGE_LOOP('',(#779,#780,#788,#794));
#796=FACE_BOUND('',#795,.T.);
#797=ADVANCED_FACE('F599',(#796),#778,.F.);
#798=CARTESIAN_POINT('',(33.55,1.8,-6.35));
#799=DIRECTION('',(0.,0.,-1.));
#800=DIRECTION('',(-1.,0.,0.));
#801=AXIS2_PLACEMENT_3D('',#798,#799,#800);
#802=PLANE('',#801);
#803=ORIENTED_EDGE('',*,*,#256,.T.);
#804=ORIENTED_EDGE('',*,*,#793,.F.);
#805=DIRECTION('',(1.,0.,0.));
#806=VECTOR('',#805,1.);
#807=CARTESIAN_POINT('',(33.55,1.8,-6.35));
#808=LINE('',#807,#806);
#809=EDGE_CURVE('E227',#730,#786,#808,.T.);
#810=ORIENTED_EDGE('',*,*,#809,.F.);
#811=ORIENTED_EDGE('',*,*,#731,.T.);
#812=EDGE_LOOP('',(#803,#804,#810,#811));
#813=FACE_BOUND('',#812,.T.);
#814=ADVANCED_FACE('F240',(#813),#802,.F.);
#815=CARTESIAN_POINT('',(33.55,1.8,-6.35));
#816=DIRECTION('',(0.,-1.,0.));
#817=DIRECTION('',(0.,0.,-1.));
#818=AXIS2_PLACEMENT_3D('',#815,#816,#817);
#819=PLANE('',#818);
#820=ORIENTED_EDGE('',*,*,#739,.T.);
#821=ORIENTED_EDGE('',*,*,#809,.T.);
#822=ORIENTED_EDGE('',*,*,#787,.T.);
#823=ORIENTED_EDGE('',*,*,#763,.T.);
#824=EDGE_LOOP('',(#820,#821,#822,#823));
#825=FACE_BOUND('',#824,.T.);
#826=ADVANCED_FACE('F226',(#825),#819,.T.);
#827=CARTESIAN_POINT('',(25.55,1.8,-6.35));
#828=DIRECTION('',(0.,-1.,0.));
#829=DIRECTION('',(0.,0.,-1.));
#830=AXIS2_PLACEMENT_3D('',#827,#828,#829);
#831=PLANE('',#830);
#832=DIRECTION('',(0.,0.,-1.));
#833=VECTOR('',#832,1.);
#834=CARTESIAN_POINT('',(25.55,1.8,-1.55));
#835=LINE('',#834,#833);
#836=CARTESIAN_POINT('',(25.55,1.8,-1.55));
#837=VERTEX_POINT('',#836);
#838=CARTESIAN_POINT('',(25.55,1.8,-6.35));
#839=VERTEX_POINT('',#838);
#840=EDGE_CURVE('E376',#837,#839,#835,.T.);
#841=ORIENTED_EDGE('',*,*,#840,.T.);
#842=DIRECTION('',(1.,0.,0.));
#843=VECTOR('',#842,1.);
#844=CARTESIAN_POINT('',(25.55,1.8,-6.35));
#845=LINE('',#844,#843);
#846=CARTESIAN_POINT('',(30.35,1.8,-6.35));
#847=VERTEX_POINT('',#846);
#848=EDGE_CURVE('E394',#839,#847,#845,.T.);
#849=ORIENTED_EDGE('',*,*,#848,.T.);
#850=DIRECTION('',(0.,0.,1.));
#851=VECTOR('',#850,1.);
#852=CARTESIAN_POINT('',(30.35,1.8,-1.55));
#853=LINE('',#852,#851);
#854=CARTESIAN_POINT('',(30.35,1.8,-1.55));
#855=VERTEX_POINT('',#854);
#856=EDGE_CURVE('E388',#847,#855,#853,.T.);
#857=ORIENTED_EDGE('',*,*,#856,.T.);
#858=DIRECTION('',(-1.,0.,0.));
#859=VECTOR('',#858,1.);
#860=CARTESIAN_POINT('',(25.55,1.8,-1.55));
#861=LINE('',#860,#859);
#862=EDGE_CURVE('E382',#855,#837,#861,.T.);
#863=ORIENTED_EDGE('',*,*,#862,.T.);
#864=EDGE_LOOP('',(#841,#849,#857,#863));
#865=FACE_BOUND('',#864,.T.);
#866=ADVANCED_FACE('F596',(#865),#831,.T.);
#867=CARTESIAN_POINT('',(25.55,1.8,-6.35));
#868=DIRECTION('',(0.,0.,-1.));
#869=DIRECTION('',(-1.,0.,0.));
#870=AXIS2_PLACEMENT_3D('',#867,#868,#869);
#871=PLANE('',#870);
#872=ORIENTED_EDGE('',*,*,#330,.T.);
#873=DIRECTION('',(0.,-1.,0.));
#874=VECTOR('',#873,1.);
#875=CARTESIAN_POINT('',(30.35,1.8,-6.35));
#876=LINE('',#875,#874);
#877=EDGE_CURVE('E391',#847,#323,#876,.T.);
#878=ORIENTED_EDGE('',*,*,#877,.F.);
#879=ORIENTED_EDGE('',*,*,#848,.F.);
#880=DIRECTION('',(0.,-1.,0.));
#881=VECTOR('',#880,1.);
#882=CARTESIAN_POINT('',(25.55,1.8,-6.35));
#883=LINE('',#882,#881);
#884=EDGE_CURVE('E373',#839,#307,#883,.T.);
#885=ORIENTED_EDGE('',*,*,#884,.T.);
#886=EDGE_LOOP('',(#872,#878,#879,#885));
#887=FACE_BOUND('',#886,.T.);
#888=ADVANCED_FACE('F610',(#887),#871,.F.);
#889=CARTESIAN_POINT('',(30.35,1.8,-1.55));
#890=DIRECTION('',(1.,0.,0.));
#891=DIRECTION('',(0.,0.,-1.));
#892=AXIS2_PLACEMENT_3D('',#889,#890,#891);
#893=PLANE('',#892);
#894=ORIENTED_EDGE('',*,*,#324,.T.);
#895=DIRECTION('',(0.,-1.,0.));
#896=VECTOR('',#895,1.);
#897=CARTESIAN_POINT('',(30.35,1.8,-1.55));
#898=LINE('',#897,#896);
#899=EDGE_CURVE('E385',#855,#315,#898,.T.);
#900=ORIENTED_EDGE('',*,*,#899,.F.);
#901=ORIENTED_EDGE('',*,*,#856,.F.);
#902=ORIENTED_EDGE('',*,*,#877,.T.);
#903=EDGE_LOOP('',(#894,#900,#901,#902));
#904=FACE_BOUND('',#903,.T.);
#905=ADVANCED_FACE('F616',(#904),#893,.F.);
#906=CARTESIAN_POINT('',(25.55,1.8,-1.55));
#907=DIRECTION('',(0.,0.,1.));
#908=DIRECTION('',(1.,0.,0.));
#909=AXIS2_PLACEMENT_3D('',#906,#907,#908);
#910=PLANE('',#909);
#911=ORIENTED_EDGE('',*,*,#316,.T.);
#912=DIRECTION('',(0.,-1.,0.));
#913=VECTOR('',#912,1.);
#914=CARTESIAN_POINT('',(25.55,1.8,-1.55));
#915=LINE('',#914,#913);
#916=EDGE_CURVE('E379',#837,#305,#915,.T.);
#917=ORIENTED_EDGE('',*,*,#916,.F.);
#918=ORIENTED_EDGE('',*,*,#862,.F.);
#919=ORIENTED_EDGE('',*,*,#899,.T.);
#920=EDGE_LOOP('',(#911,#917,#918,#919));
#921=FACE_BOUND('',#920,.T.);
#922=ADVANCED_FACE('F719',(#921),#910,.F.);
#923=CARTESIAN_POINT('',(25.55,1.8,-1.55));
#924=DIRECTION('',(-1.,0.,0.));
#925=DIRECTION('',(0.,0.,1.));
#926=AXIS2_PLACEMENT_3D('',#923,#924,#925);
#927=PLANE('',#926);
#928=ORIENTED_EDGE('',*,*,#308,.T.);
#929=ORIENTED_EDGE('',*,*,#884,.F.);
#930=ORIENTED_EDGE('',*,*,#840,.F.);
#931=ORIENTED_EDGE('',*,*,#916,.T.);
#932=EDGE_LOOP('',(#928,#929,#930,#931));
#933=FACE_BOUND('',#932,.T.);
#934=ADVANCED_FACE('F641',(#933),#927,.F.);
#935=CARTESIAN_POINT('',(17.55,1.8,-6.35));
#936=DIRECTION('',(0.,-1.,0.));
#937=DIRECTION('',(0.,0.,-1.));
#938=AXIS2_PLACEMENT_3D('',#935,#936,#937);
#939=PLANE('',#938);
#940=DIRECTION('',(0.,0.,-1.));
#941=VECTOR('',#940,1.);
#942=CARTESIAN_POINT('',(17.55,1.8,-1.55));
#943=LINE('',#942,#941);
#944=CARTESIAN_POINT('',(17.55,1.8,-1.55));
#945=VERTEX_POINT('',#944);
#946=CARTESIAN_POINT('',(17.55,1.8,-6.35));
#947=VERTEX_POINT('',#946);
#948=EDGE_CURVE('E411',#945,#947,#943,.T.);
#949=ORIENTED_EDGE('',*,*,#948,.T.);
#950=DIRECTION('',(1.,0.,0.));
#951=VECTOR('',#950,1.);
#952=CARTESIAN_POINT('',(17.55,1.8,-6.35));
#953=LINE('',#952,#951);
#954=CARTESIAN_POINT('',(22.35,1.8,-6.35));
#955=VERTEX_POINT('',#954);
#956=EDGE_CURVE('E429',#947,#955,#953,.T.);
#957=ORIENTED_EDGE('',*,*,#956,.T.);
#958=DIRECTION('',(0.,0.,1.));
#959=VECTOR('',#958,1.);
#960=CARTESIAN_POINT('',(22.35,1.8,-1.55));
#961=LINE('',#960,#959);
#962=CARTESIAN_POINT('',(22.35,1.8,-1.55));
#963=VERTEX_POINT('',#962);
#964=EDGE_CURVE('E423',#955,#963,#961,.T.);
#965=ORIENTED_EDGE('',*,*,#964,.T.);
#966=DIRECTION('',(-1.,0.,0.));
#967=VECTOR('',#966,1.);
#968=CARTESIAN_POINT('',(17.55,1.8,-1.55));
#969=LINE('',#968,#967);
#970=EDGE_CURVE('E417',#963,#945,#969,.T.);
#971=ORIENTED_EDGE('',*,*,#970,.T.);
#972=EDGE_LOOP('',(#949,#957,#965,#971));
#973=FACE_BOUND('',#972,.T.);
#974=ADVANCED_FACE('F637',(#973),#939,.T.);
#975=CARTESIAN_POINT('',(17.55,1.8,-6.35));
#976=DIRECTION('',(0.,0.,-1.));
#977=DIRECTION('',(-1.,0.,0.));
#978=AXIS2_PLACEMENT_3D('',#975,#976,#977);
#979=PLANE('',#978);
#980=ORIENTED_EDGE('',*,*,#364,.T.);
#981=DIRECTION('',(0.,-1.,0.));
#982=VECTOR('',#981,1.);
#983=CARTESIAN_POINT('',(22.35,1.8,-6.35));
#984=LINE('',#983,#982);
#985=EDGE_CURVE('E426',#955,#357,#984,.T.);
#986=ORIENTED_EDGE('',*,*,#985,.F.);
#987=ORIENTED_EDGE('',*,*,#956,.F.);
#988=DIRECTION('',(0.,-1.,0.));
#989=VECTOR('',#988,1.);
#990=CARTESIAN_POINT('',(17.55,1.8,-6.35));
#991=LINE('',#990,#989);
#992=EDGE_CURVE('E408',#947,#341,#991,.T.);
#993=ORIENTED_EDGE('',*,*,#992,.T.);
#994=EDGE_LOOP('',(#980,#986,#987,#993));
#995=FACE_BOUND('',#994,.T.);
#996=ADVANCED_FACE('F633',(#995),#979,.F.);
#997=CARTESIAN_POINT('',(22.35,1.8,-1.55));
#998=DIRECTION('',(1.,0.,0.));
#999=DIRECTION('',(0.,0.,-1.));
#1000=AXIS2_PLACEMENT_3D('',#997,#998,#999);
#1001=PLANE('',#1000);
#1002=ORIENTED_EDGE('',*,*,#358,.T.);
#1003=DIRECTION('',(0.,-1.,0.));
#1004=VECTOR('',#1003,1.);
#1005=CARTESIAN_POINT('',(22.35,1.8,-1.55));
#1006=LINE('',#1005,#1004);
#1007=EDGE_CURVE('E420',#963,#349,#1006,.T.);
#1008=ORIENTED_EDGE('',*,*,#1007,.F.);
#1009=ORIENTED_EDGE('',*,*,#964,.F.);
#1010=ORIENTED_EDGE('',*,*,#985,.T.);
#1011=EDGE_LOOP('',(#1002,#1008,#1009,#1010));
#1012=FACE_BOUND('',#1011,.T.);
#1013=ADVANCED_FACE('F629',(#1012),#1001,.F.);
#1014=CARTESIAN_POINT('',(17.55,1.8,-1.55));
#1015=DIRECTION('',(0.,0.,1.));
#1016=DIRECTION('',(1.,0.,0.));
#1017=AXIS2_PLACEMENT_3D('',#1014,#1015,#1016);
#1018=PLANE('',#1017);
#1019=ORIENTED_EDGE('',*,*,#350,.T.);
#1020=DIRECTION('',(0.,-1.,0.));
#1021=VECTOR('',#1020,1.);
#1022=CARTESIAN_POINT('',(17.55,1.8,-1.55));
#1023=LINE('',#1022,#1021);
#1024=EDGE_CURVE('E414',#945,#339,#1023,.T.);
#1025=ORIENTED_EDGE('',*,*,#1024,.F.);
#1026=ORIENTED_EDGE('',*,*,#970,.F.);
#1027=ORIENTED_EDGE('',*,*,#1007,.T.);
#1028=EDGE_LOOP('',(#1019,#1025,#1026,#1027));
#1029=FACE_BOUND('',#1028,.T.);
#1030=ADVANCED_FACE('F625',(#1029),#1018,.F.);
#1031=CARTESIAN_POINT('',(17.55,1.8,-1.55));
#1032=DIRECTION('',(-1.,0.,0.));
#1033=DIRECTION('',(0.,0.,1.));
#1034=AXIS2_PLACEMENT_3D('',#1031,#1032,#1033);
#1035=PLANE('',#1034);
#1036=ORIENTED_EDGE('',*,*,#342,.T.);
#1037=ORIENTED_EDGE('',*,*,#992,.F.);
#1038=ORIENTED_EDGE('',*,*,#948,.F.);
#1039=ORIENTED_EDGE('',*,*,#1024,.T.);
#1040=EDGE_LOOP('',(#1036,#1037,#1038,#1039));
#1041=FACE_BOUND('',#1040,.T.);
#1042=ADVANCED_FACE('F621',(#1041),#1035,.F.);
#1043=CARTESIAN_POINT('',(9.55,1.8,-6.35));
#1044=DIRECTION('',(0.,-1.,0.));
#1045=DIRECTION('',(0.,0.,-1.));
#1046=AXIS2_PLACEMENT_3D('',#1043,#1044,#1045);
#1047=PLANE('',#1046);
#1048=DIRECTION('',(0.,0.,-1.));
#1049=VECTOR('',#1048,1.);
#1050=CARTESIAN_POINT('',(9.55,1.8,-1.55));
#1051=LINE('',#1050,#1049);
#1052=CARTESIAN_POINT('',(9.55,1.8,-1.55));
#1053=VERTEX_POINT('',#1052);
#1054=CARTESIAN_POINT('',(9.55,1.8,-6.35));
#1055=VERTEX_POINT('',#1054);
#1056=EDGE_CURVE('E446',#1053,#1055,#1051,.T.);
#1057=ORIENTED_EDGE('',*,*,#1056,.T.);
#1058=DIRECTION('',(1.,0.,0.));
#1059=VECTOR('',#1058,1.);
#1060=CARTESIAN_POINT('',(9.55,1.8,-6.35));
#1061=LINE('',#1060,#1059);
#1062=CARTESIAN_POINT('',(14.35,1.8,-6.35));
#1063=VERTEX_POINT('',#1062);
#1064=EDGE_CURVE('E464',#1055,#1063,#1061,.T.);
#1065=ORIENTED_EDGE('',*,*,#1064,.T.);
#1066=DIRECTION('',(0.,0.,1.));
#1067=VECTOR('',#1066,1.);
#1068=CARTESIAN_POINT('',(14.35,1.8,-1.55));
#1069=LINE('',#1068,#1067);
#1070=CARTESIAN_POINT('',(14.35,1.8,-1.55));
#1071=VERTEX_POINT('',#1070);
#1072=EDGE_CURVE('E458',#1063,#1071,#1069,.T.);
#1073=ORIENTED_EDGE('',*,*,#1072,.T.);
#1074=DIRECTION('',(-1.,0.,0.));
#1075=VECTOR('',#1074,1.);
#1076=CARTESIAN_POINT('',(9.55,1.8,-1.55));
#1077=LINE('',#1076,#1075);
#1078=EDGE_CURVE('E452',#1071,#1053,#1077,.T.);
#1079=ORIENTED_EDGE('',*,*,#1078,.T.);
#1080=EDGE_LOOP('',(#1057,#1065,#1073,#1079));
#1081=FACE_BOUND('',#1080,.T.);
#1082=ADVANCED_FACE('F624',(#1081),#1047,.T.);
#1083=CARTESIAN_POINT('',(9.55,1.8,-6.35));
#1084=DIRECTION('',(0.,0.,-1.));
#1085=DIRECTION('',(-1.,0.,0.));
#1086=AXIS2_PLACEMENT_3D('',#1083,#1084,#1085);
#1087=PLANE('',#1086);
#1088=ORIENTED_EDGE('',*,*,#398,.T.);
#1089=DIRECTION('',(0.,-1.,0.));
#1090=VECTOR('',#1089,1.);
#1091=CARTESIAN_POINT('',(14.35,1.8,-6.35));
#1092=LINE('',#1091,#1090);
#1093=EDGE_CURVE('E461',#1063,#391,#1092,.T.);
#1094=ORIENTED_EDGE('',*,*,#1093,.F.);
#1095=ORIENTED_EDGE('',*,*,#1064,.F.);
#1096=DIRECTION('',(0.,-1.,0.));
#1097=VECTOR('',#1096,1.);
#1098=CARTESIAN_POINT('',(9.55,1.8,-6.35));
#1099=LINE('',#1098,#1097);
#1100=EDGE_CURVE('E443',#1055,#375,#1099,.T.);
#1101=ORIENTED_EDGE('',*,*,#1100,.T.);
#1102=EDGE_LOOP('',(#1088,#1094,#1095,#1101));
#1103=FACE_BOUND('',#1102,.T.);
#1104=ADVANCED_FACE('F654',(#1103),#1087,.F.);
#1105=CARTESIAN_POINT('',(14.35,1.8,-1.55));
#1106=DIRECTION('',(1.,0.,0.));
#1107=DIRECTION('',(0.,0.,-1.));
#1108=AXIS2_PLACEMENT_3D('',#1105,#1106,#1107);
#1109=PLANE('',#1108);
#1110=ORIENTED_EDGE('',*,*,#392,.T.);
#1111=DIRECTION('',(0.,-1.,0.));
#1112=VECTOR('',#1111,1.);
#1113=CARTESIAN_POINT('',(14.35,1.8,-1.55));
#1114=LINE('',#1113,#1112);
#1115=EDGE_CURVE('E455',#1071,#383,#1114,.T.);
#1116=ORIENTED_EDGE('',*,*,#1115,.F.);
#1117=ORIENTED_EDGE('',*,*,#1072,.F.);
#1118=ORIENTED_EDGE('',*,*,#1093,.T.);
#1119=EDGE_LOOP('',(#1110,#1116,#1117,#1118));
#1120=FACE_BOUND('',#1119,.T.);
#1121=ADVANCED_FACE('F650',(#1120),#1109,.F.);
#1122=CARTESIAN_POINT('',(9.55,1.8,-1.55));
#1123=DIRECTION('',(0.,0.,1.));
#1124=DIRECTION('',(1.,0.,0.));
#1125=AXIS2_PLACEMENT_3D('',#1122,#1123,#1124);
#1126=PLANE('',#1125);
#1127=ORIENTED_EDGE('',*,*,#384,.T.);
#1128=DIRECTION('',(0.,-1.,0.));
#1129=VECTOR('',#1128,1.);
#1130=CARTESIAN_POINT('',(9.55,1.8,-1.55));
#1131=LINE('',#1130,#1129);
#1132=EDGE_CURVE('E449',#1053,#373,#1131,.T.);
#1133=ORIENTED_EDGE('',*,*,#1132,.F.);
#1134=ORIENTED_EDGE('',*,*,#1078,.F.);
#1135=ORIENTED_EDGE('',*,*,#1115,.T.);
#1136=EDGE_LOOP('',(#1127,#1133,#1134,#1135));
#1137=FACE_BOUND('',#1136,.T.);
#1138=ADVANCED_FACE('F646',(#1137),#1126,.F.);
#1139=CARTESIAN_POINT('',(9.55,1.8,-1.55));
#1140=DIRECTION('',(-1.,0.,0.));
#1141=DIRECTION('',(0.,0.,1.));
#1142=AXIS2_PLACEMENT_3D('',#1139,#1140,#1141);
#1143=PLANE('',#1142);
#1144=ORIENTED_EDGE('',*,*,#376,.T.);
#1145=ORIENTED_EDGE('',*,*,#1100,.F.);
#1146=ORIENTED_EDGE('',*,*,#1056,.F.);
#1147=ORIENTED_EDGE('',*,*,#1132,.T.);
#1148=EDGE_LOOP('',(#1144,#1145,#1146,#1147));
#1149=FACE_BOUND('',#1148,.T.);
#1150=ADVANCED_FACE('F643',(#1149),#1143,.F.);
#1151=CARTESIAN_POINT('',(1.55,1.8,-6.35));
#1152=DIRECTION('',(0.,-1.,0.));
#1153=DIRECTION('',(0.,0.,-1.));
#1154=AXIS2_PLACEMENT_3D('',#1151,#1152,#1153);
#1155=PLANE('',#1154);
#1156=DIRECTION('',(0.,0.,-1.));
#1157=VECTOR('',#1156,1.);
#1158=CARTESIAN_POINT('',(1.55,1.8,-1.55));
#1159=LINE('',#1158,#1157);
#1160=CARTESIAN_POINT('',(1.55,1.8,-1.55));
#1161=VERTEX_POINT('',#1160);
#1162=CARTESIAN_POINT('',(1.55,1.8,-6.35));
#1163=VERTEX_POINT('',#1162);
#1164=EDGE_CURVE('E481',#1161,#1163,#1159,.T.);
#1165=ORIENTED_EDGE('',*,*,#1164,.T.);
#1166=DIRECTION('',(1.,0.,0.));
#1167=VECTOR('',#1166,1.);
#1168=CARTESIAN_POINT('',(1.55,1.8,-6.35));
#1169=LINE('',#1168,#1167);
#1170=CARTESIAN_POINT('',(6.34999999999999,1.8,-6.35));
#1171=VERTEX_POINT('',#1170);
#1172=EDGE_CURVE('E11',#1163,#1171,#1169,.T.);
#1173=ORIENTED_EDGE('',*,*,#1172,.T.);
#1174=DIRECTION('',(0.,0.,1.));
#1175=VECTOR('',#1174,1.);
#1176=CARTESIAN_POINT('',(6.34999999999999,1.8,-1.55));
#1177=LINE('',#1176,#1175);
#1178=CARTESIAN_POINT('',(6.34999999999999,1.8,-1.55));
#1179=VERTEX_POINT('',#1178);
#1180=EDGE_CURVE('E52',#1171,#1179,#1177,.T.);
#1181=ORIENTED_EDGE('',*,*,#1180,.T.);
#1182=DIRECTION('',(-1.,0.,0.));
#1183=VECTOR('',#1182,1.);
#1184=CARTESIAN_POINT('',(1.55,1.8,-1.55));
#1185=LINE('',#1184,#1183);
#1186=EDGE_CURVE('E60',#1179,#1161,#1185,.T.);
#1187=ORIENTED_EDGE('',*,*,#1186,.T.);
#1188=EDGE_LOOP('',(#1165,#1173,#1181,#1187));
#1189=FACE_BOUND('',#1188,.T.);
#1190=ADVANCED_FACE('F39',(#1189),#1155,.T.);
#1191=CARTESIAN_POINT('',(1.55,1.8,-6.35));
#1192=DIRECTION('',(0.,0.,-1.));
#1193=DIRECTION('',(-1.,0.,0.));
#1194=AXIS2_PLACEMENT_3D('',#1191,#1192,#1193);
#1195=PLANE('',#1194);
#1196=ORIENTED_EDGE('',*,*,#432,.T.);
#1197=DIRECTION('',(0.,-1.,0.));
#1198=VECTOR('',#1197,1.);
#1199=CARTESIAN_POINT('',(6.34999999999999,1.8,-6.35));
#1200=LINE('',#1199,#1198);
#1201=EDGE_CURVE('E45',#1171,#425,#1200,.T.);
#1202=ORIENTED_EDGE('',*,*,#1201,.F.);
#1203=ORIENTED_EDGE('',*,*,#1172,.F.);
#1204=DIRECTION('',(0.,-1.,0.));
#1205=VECTOR('',#1204,1.);
#1206=CARTESIAN_POINT('',(1.55,1.8,-6.35));
#1207=LINE('',#1206,#1205);
#1208=EDGE_CURVE('E478',#1163,#409,#1207,.T.);
#1209=ORIENTED_EDGE('',*,*,#1208,.T.);
#1210=EDGE_LOOP('',(#1196,#1202,#1203,#1209));
#1211=FACE_BOUND('',#1210,.T.);
#1212=ADVANCED_FACE('F493',(#1211),#1195,.F.);
#1213=CARTESIAN_POINT('',(6.34999999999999,1.8,-1.55));
#1214=DIRECTION('',(1.,0.,0.));
#1215=DIRECTION('',(0.,0.,-1.));
#1216=AXIS2_PLACEMENT_3D('',#1213,#1214,#1215);
#1217=PLANE('',#1216);
#1218=ORIENTED_EDGE('',*,*,#426,.T.);
#1219=DIRECTION('',(0.,-1.,0.));
#1220=VECTOR('',#1219,1.);
#1221=CARTESIAN_POINT('',(6.34999999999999,1.8,-1.55));
#1222=LINE('',#1221,#1220);
#1223=EDGE_CURVE('E488',#1179,#417,#1222,.T.);
#1224=ORIENTED_EDGE('',*,*,#1223,.F.);
#1225=ORIENTED_EDGE('',*,*,#1180,.F.);
#1226=ORIENTED_EDGE('',*,*,#1201,.T.);
#1227=EDGE_LOOP('',(#1218,#1224,#1225,#1226));
#1228=FACE_BOUND('',#1227,.T.);
#1229=ADVANCED_FACE('F490',(#1228),#1217,.F.);
#1230=CARTESIAN_POINT('',(1.55,1.8,-1.55));
#1231=DIRECTION('',(0.,0.,1.));
#1232=DIRECTION('',(1.,0.,0.));
#1233=AXIS2_PLACEMENT_3D('',#1230,#1231,#1232);
#1234=PLANE('',#1233);
#1235=ORIENTED_EDGE('',*,*,#418,.T.);
#1236=DIRECTION('',(0.,-1.,0.));
#1237=VECTOR('',#1236,1.);
#1238=CARTESIAN_POINT('',(1.55,1.8,-1.55));
#1239=LINE('',#1238,#1237);
#1240=EDGE_CURVE('E484',#1161,#407,#1239,.T.);
#1241=ORIENTED_EDGE('',*,*,#1240,.F.);
#1242=ORIENTED_EDGE('',*,*,#1186,.F.);
#1243=ORIENTED_EDGE('',*,*,#1223,.T.);
#1244=EDGE_LOOP('',(#1235,#1241,#1242,#1243));
#1245=FACE_BOUND('',#1244,.T.);
#1246=ADVANCED_FACE('F498',(#1245),#1234,.F.);
#1247=CARTESIAN_POINT('',(1.55,1.8,-1.55));
#1248=DIRECTION('',(-1.,0.,0.));
#1249=DIRECTION('',(0.,0.,1.));
#1250=AXIS2_PLACEMENT_3D('',#1247,#1248,#1249);
#1251=PLANE('',#1250);
#1252=ORIENTED_EDGE('',*,*,#410,.T.);
#1253=ORIENTED_EDGE('',*,*,#1208,.F.);
#1254=ORIENTED_EDGE('',*,*,#1164,.F.);
#1255=ORIENTED_EDGE('',*,*,#1240,.T.);
#1256=EDGE_LOOP('',(#1252,#1253,#1254,#1255));
#1257=FACE_BOUND('',#1256,.T.);
#1258=ADVANCED_FACE('F497',(#1257),#1251,.F.);
#1259=CLOSED_SHELL('',(#124,#155,#179,#203,#220,#436,#456,#465,#496,#520,#544,#561,#573,#593,
#602,#622,#631,#651,#660,#680,#689,#709,#718,#749,#773,#797,#814,#826,#866,#888,#905,#922,#934,
#974,#996,#1013,#1030,#1042,#1082,#1104,#1121,#1138,#1150,#1190,#1212,#1229,#1246,#1258));
#1260=MANIFOLD_SOLID_BREP('B2',#1259);
#1261=ADVANCED_BREP_SHAPE_REPRESENTATION('',(#18,#1260),#14);
#1262=SHAPE_DEFINITION_REPRESENTATION(#9,#1261);
ENDSEC;
END-ISO-10303-21;
